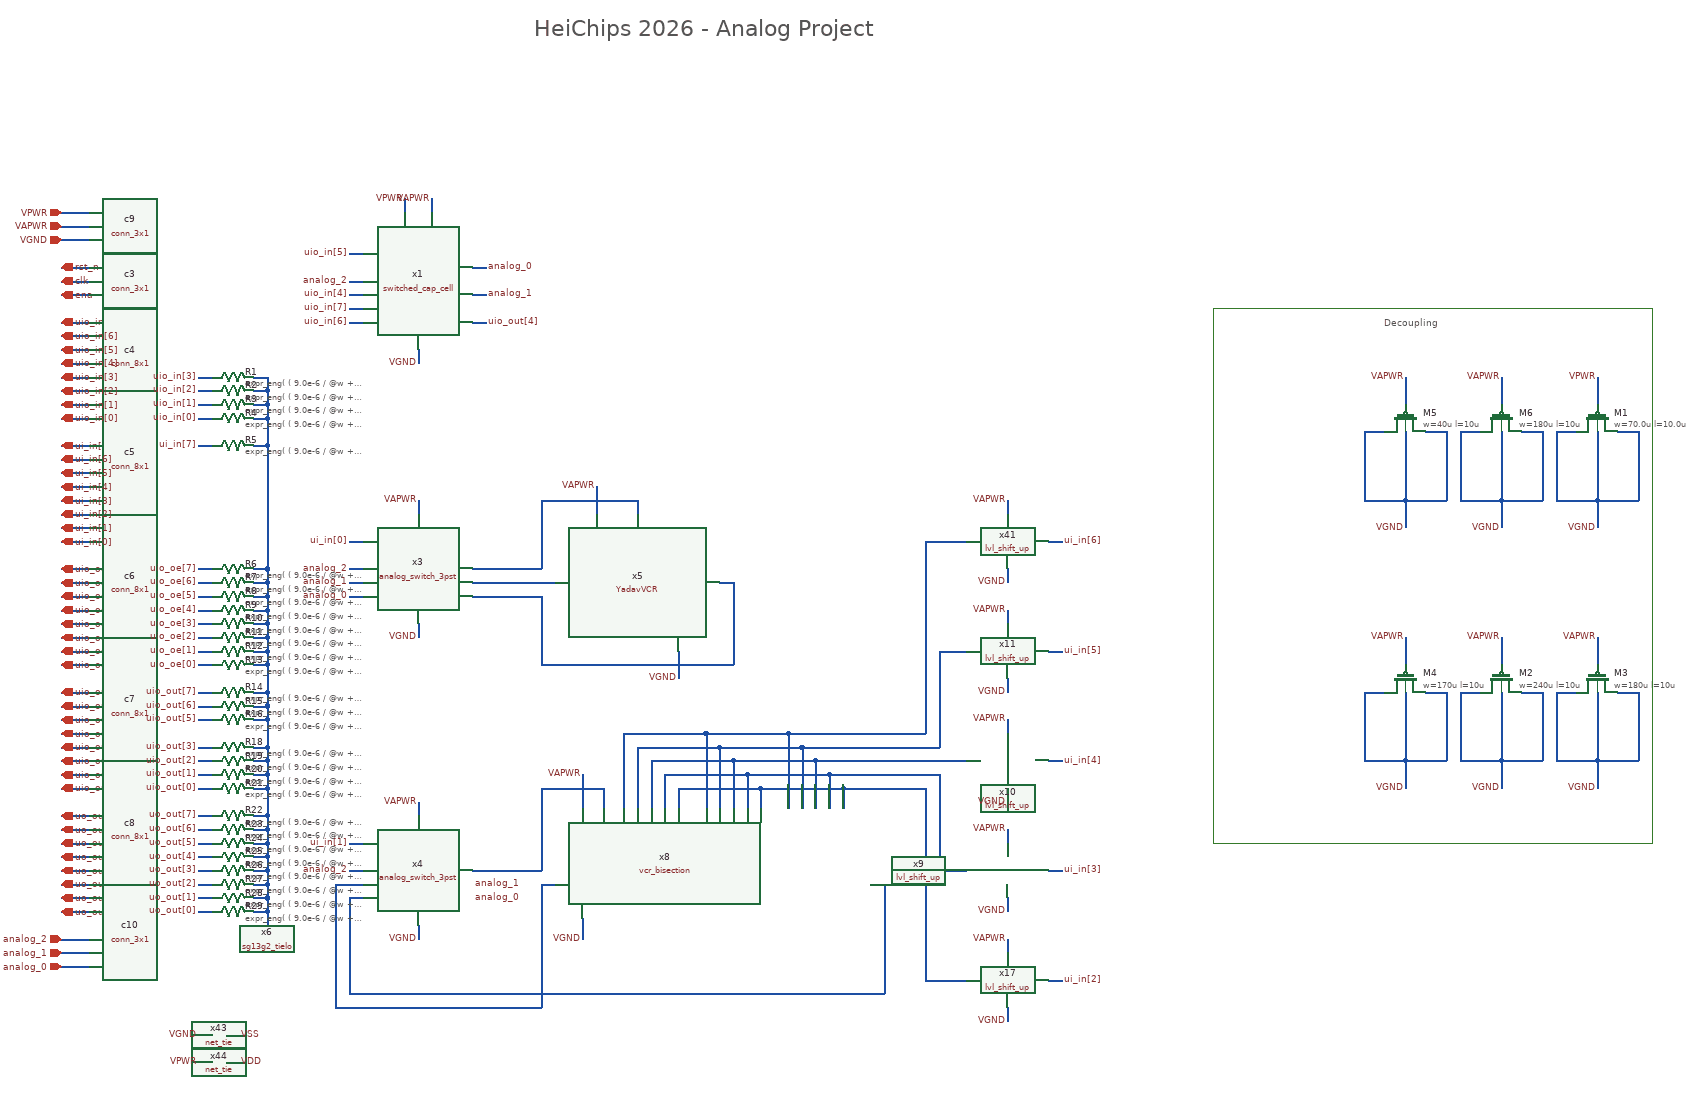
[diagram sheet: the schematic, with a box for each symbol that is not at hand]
v {xschem version=3.4.8RC file_version=1.3}
G {}
K {}
V {}
S {}
F {}
E {}
P 4 1 2050 -1280 {}
P 4 6 1820 -1280 1820 -1280 2460 -1280 2460 -500 1820 -500 1820 -1280 {fill = false
dash = 16}
T {HeiChips 2026 - Analog Project} 830 -1700 0 0 1 1 {}
T {Decoupling} 2070 -1270 0 0 0.4 0.4 {}
N 2380 -800 2380 -760 {lab=VAPWR
}
N 2320 -720 2350 -720 {lab=VGND
}
N 2320 -720 2320 -620 {lab=VGND
}
N 2380 -620 2440 -620 {lab=VGND
}
N 2440 -720 2440 -620 {lab=VGND
}
N 2410 -720 2440 -720 {lab=VGND
}
N 2380 -620 2380 -580 {lab=VGND
}
N 2380 -720 2380 -620 {lab=VGND
}
N 2320 -620 2380 -620 {lab=VGND
}
N 140 -1320 180 -1320 {lab=clk}
N 140 -1300 180 -1300 {lab=ena}
N 140 -1340 180 -1340 {lab=rst_n}
N 140 -1260 180 -1260 {lab=uio_in[7]}
N 140 -1240 180 -1240 {lab=uio_in[6]}
N 140 -1220 180 -1220 {lab=uio_in[5]}
N 140 -1200 180 -1200 {lab=uio_in[4]}
N 140 -1180 180 -1180 {lab=uio_in[3]}
N 140 -1160 180 -1160 {lab=uio_in[2]}
N 140 -1140 180 -1140 {lab=uio_in[1]}
N 140 -1120 180 -1120 {lab=uio_in[0]}
N 140 -1080 180 -1080 {lab=ui_in[7]}
N 140 -1060 180 -1060 {lab=ui_in[6]}
N 140 -1040 180 -1040 {lab=ui_in[5]}
N 140 -1020 180 -1020 {lab=ui_in[4]}
N 140 -1000 180 -1000 {lab=ui_in[3]}
N 140 -980 180 -980 {lab=ui_in[2]}
N 140 -960 180 -960 {lab=ui_in[1]}
N 140 -940 180 -940 {lab=ui_in[0]}
N 140 -900 180 -900 {lab=uio_oe[7]}
N 140 -880 180 -880 {lab=uio_oe[6]}
N 140 -860 180 -860 {lab=uio_oe[5]}
N 140 -840 180 -840 {lab=uio_oe[4]}
N 140 -820 180 -820 {lab=uio_oe[3]}
N 140 -800 180 -800 {lab=uio_oe[2]}
N 140 -780 180 -780 {lab=uio_oe[1]}
N 140 -760 180 -760 {lab=uio_oe[0]}
N 140 -720 180 -720 {lab=uio_out[7]}
N 140 -700 180 -700 {lab=uio_out[6]}
N 140 -680 180 -680 {lab=uio_out[5]}
N 140 -660 180 -660 {lab=uio_out[4]}
N 140 -640 180 -640 {lab=uio_out[3]}
N 140 -620 180 -620 {lab=uio_out[2]}
N 140 -600 180 -600 {lab=uio_out[1]}
N 140 -580 180 -580 {lab=uio_out[0]}
N 140 -540 180 -540 {lab=uo_out[7]}
N 140 -520 180 -520 {lab=uo_out[6]}
N 140 -500 180 -500 {lab=uo_out[5]}
N 140 -480 180 -480 {lab=uo_out[4]}
N 140 -460 180 -460 {lab=uo_out[3]}
N 140 -440 180 -440 {lab=uo_out[2]}
N 140 -420 180 -420 {lab=uo_out[1]}
N 140 -400 180 -400 {lab=uo_out[0]}
N 140 -1400 180 -1400 {lab=VAPWR}
N 140 -1380 180 -1380 {lab=VGND}
N 140 -1420 180 -1420 {lab=VPWR}
N 140 -360 180 -360 {lab=analog_2}
N 140 -340 180 -340 {lab=analog_1}
N 140 -320 180 -320 {lab=analog_0}
N 2380 -1180 2380 -1140 {lab=VPWR
}
N 2320 -1100 2350 -1100 {lab=VGND
}
N 2320 -1100 2320 -1000 {lab=VGND
}
N 2380 -1000 2440 -1000 {lab=VGND
}
N 2440 -1100 2440 -1000 {lab=VGND
}
N 2410 -1100 2440 -1100 {lab=VGND
}
N 2380 -1000 2380 -960 {lab=VGND
}
N 2380 -1100 2380 -1000 {lab=VGND
}
N 2320 -1000 2380 -1000 {lab=VGND
}
N 560 -1360 580 -1360 {lab=uio_in[5]}
N 560 -1300 580 -1300 {lab=uio_in[4]}
N 560 -1280 580 -1280 {lab=uio_in[7]}
N 560 -1260 580 -1260 {lab=uio_in[6]}
N 740 -1260 760 -1260 {lab=uio_out[4]}
N 640 -1440 640 -1420 {lab=VPWR}
N 680 -1440 680 -1420 {lab=VAPWR}
N 660 -1220 660 -1200 {lab=VGND}
N 740 -1340 760 -1340 {lab=analog_0}
N 740 -1300 760 -1300 {lab=analog_1}
N 920 -1020 920 -980 {lab=VAPWR}
N 1040 -780 1040 -740 {lab=VGND}
N 840 -760 1120 -760 {lab=#net1}
N 1100 -880 1120 -880 {lab=#net1}
N 1120 -880 1120 -760 {lab=#net1}
N 740 -880 860 -880 {lab=#net2}
N 660 -1000 660 -980 {lab=VAPWR}
N 660 -820 660 -800 {lab=VGND}
N 560 -860 580 -860 {lab=analog_0}
N 560 -880 580 -880 {lab=analog_1}
N 560 -940 580 -940 {lab=ui_in[0]}
N 560 -900 580 -900 {lab=analog_2}
N 740 -900 840 -900 {lab=#net3}
N 840 -1000 840 -900 {lab=#net3}
N 840 -1000 980 -1000 {lab=#net3}
N 980 -1000 980 -980 {lab=#net3}
N 740 -860 840 -860 {lab=#net1}
N 840 -860 840 -760 {lab=#net1}
N 660 -560 660 -540 {lab=VAPWR
}
N 660 -380 660 -360 {lab=VGND
}
N 560 -500 580 -500 {lab=ui_in[1]
}
N 560 -460 580 -460 {lab=analog_2
}
N 1340 -440 1340 -280 {lab=#net4
}
N 1320 -440 1340 -440 {lab=#net4
}
N 740 -460 840 -460 {lab=#net5
}
N 840 -580 840 -460 {lab=#net5
}
N 840 -580 930 -580 {lab=#net5
}
N 930 -580 930 -550 {lab=#net5
}
N 900 -390 900 -360 {lab=VGND
}
N 900 -600 900 -550 {lab=VAPWR
}
N 560 -1320 580 -1320 {lab=analog_2}
N 340 -400 360 -400 {lab=uo_out[0]
}
N 340 -420 360 -420 {lab=uo_out[1]
}
N 340 -440 360 -440 {lab=uo_out[2]
}
N 340 -460 360 -460 {lab=uo_out[3]
}
N 340 -480 360 -480 {lab=uo_out[4]
}
N 340 -500 360 -500 {lab=uo_out[5]
}
N 340 -520 360 -520 {lab=uo_out[6]
}
N 420 -520 440 -520 {lab=#net6
}
N 440 -520 440 -500 {lab=#net6
}
N 420 -500 440 -500 {lab=#net6
}
N 440 -500 440 -480 {lab=#net6
}
N 420 -480 440 -480 {lab=#net6
}
N 440 -480 440 -460 {lab=#net6
}
N 420 -460 440 -460 {lab=#net6
}
N 440 -460 440 -440 {lab=#net6
}
N 420 -440 440 -440 {lab=#net6
}
N 440 -440 440 -420 {lab=#net6
}
N 420 -420 440 -420 {lab=#net6
}
N 440 -420 440 -400 {lab=#net6
}
N 420 -400 440 -400 {lab=#net6
}
N 440 -400 440 -380 {lab=#net6
}
N 340 -580 360 -580 {lab=uio_out[0]
}
N 340 -600 360 -600 {lab=uio_out[1]
}
N 340 -620 360 -620 {lab=uio_out[2]
}
N 340 -640 360 -640 {lab=uio_out[3]
}
N 340 -680 360 -680 {lab=uio_out[5]
}
N 340 -700 360 -700 {lab=uio_out[6]
}
N 420 -700 440 -700 {lab=#net6
}
N 440 -700 440 -680 {lab=#net6
}
N 420 -680 440 -680 {lab=#net6
}
N 420 -640 440 -640 {lab=#net6
}
N 440 -640 440 -620 {lab=#net6
}
N 420 -620 440 -620 {lab=#net6
}
N 440 -620 440 -600 {lab=#net6
}
N 420 -600 440 -600 {lab=#net6
}
N 440 -600 440 -580 {lab=#net6
}
N 420 -580 440 -580 {lab=#net6
}
N 440 -580 440 -540 {lab=#net6
}
N 340 -720 360 -720 {lab=uio_out[7]
}
N 420 -720 440 -720 {lab=#net6
}
N 340 -1120 360 -1120 {lab=uio_in[0]
}
N 340 -1140 360 -1140 {lab=uio_in[1]
}
N 340 -1160 360 -1160 {lab=uio_in[2]
}
N 340 -1180 360 -1180 {lab=uio_in[3]
}
N 420 -1180 440 -1180 {lab=#net6
}
N 440 -1180 440 -1160 {lab=#net6
}
N 420 -1160 440 -1160 {lab=#net6
}
N 440 -1160 440 -1140 {lab=#net6
}
N 420 -1140 440 -1140 {lab=#net6
}
N 440 -1140 440 -1120 {lab=#net6
}
N 420 -1120 440 -1120 {lab=#net6
}
N 440 -1120 440 -1080 {lab=#net6
}
N 340 -1080 360 -1080 {lab=ui_in[7]
}
N 420 -1080 440 -1080 {lab=#net6
}
N 340 -760 360 -760 {lab=uio_oe[0]
}
N 340 -780 360 -780 {lab=uio_oe[1]
}
N 340 -800 360 -800 {lab=uio_oe[2]
}
N 340 -820 360 -820 {lab=uio_oe[3]
}
N 340 -840 360 -840 {lab=uio_oe[4]
}
N 340 -860 360 -860 {lab=uio_oe[5]
}
N 340 -880 360 -880 {lab=uio_oe[6]
}
N 420 -880 440 -880 {lab=#net6
}
N 440 -880 440 -860 {lab=#net6
}
N 420 -860 440 -860 {lab=#net6
}
N 440 -860 440 -840 {lab=#net6
}
N 420 -840 440 -840 {lab=#net6
}
N 440 -840 440 -820 {lab=#net6
}
N 420 -820 440 -820 {lab=#net6
}
N 440 -820 440 -800 {lab=#net6
}
N 420 -800 440 -800 {lab=#net6
}
N 440 -800 440 -780 {lab=#net6
}
N 420 -780 440 -780 {lab=#net6
}
N 440 -780 440 -760 {lab=#net6
}
N 420 -760 440 -760 {lab=#net6
}
N 440 -760 440 -720 {lab=#net6
}
N 340 -900 360 -900 {lab=uio_oe[7]
}
N 420 -900 440 -900 {lab=#net6
}
N 440 -900 440 -880 {lab=#net6
}
N 440 -720 440 -700 {lab=#net6
}
N 340 -220 360 -220 {lab=VGND}
N 380 -220 400 -220 {lab=VSS}
N 340 -180 360 -180 {lab=VPWR}
N 380 -180 400 -180 {lab=VDD}
N 1200 -660 1400 -660 {lab=#net7}
N 1220 -640 1420 -640 {lab=#net8}
N 1240 -620 1460 -620 {lab=#net9}
N 1260 -600 1420 -600 {lab=#net10}
N 1280 -580 1400 -580 {lab=#net11}
N 440 -1080 440 -900 {lab=#net6
}
N 560 -280 1340 -280 {lab=#net4}
N 560 -420 560 -280 {lab=#net4}
N 560 -420 580 -420 {lab=#net4}
N 840 -440 860 -440 {lab=#net12}
N 840 -440 840 -260 {lab=#net12}
N 540 -260 840 -260 {lab=#net12}
N 540 -440 540 -260 {lab=#net12}
N 540 -440 580 -440 {lab=#net12}
N 1280 -580 1280 -550 {lab=#net11}
N 1160 -580 1280 -580 {lab=#net11}
N 1260 -600 1260 -550 {lab=#net10}
N 1140 -600 1260 -600 {lab=#net10}
N 1240 -620 1240 -550 {lab=#net9}
N 1120 -620 1240 -620 {lab=#net9}
N 1220 -640 1220 -550 {lab=#net8}
N 1100 -640 1220 -640 {lab=#net8}
N 1200 -660 1200 -550 {lab=#net7}
N 1080 -660 1200 -660 {lab=#net7}
N 1160 -580 1160 -550 {lab=#net11}
N 1140 -600 1140 -550 {lab=#net10}
N 1120 -620 1120 -550 {lab=#net9}
N 1100 -640 1100 -550 {lab=#net8}
N 1080 -660 1080 -550 {lab=#net7}
N 1040 -580 1160 -580 {lab=#net11}
N 1020 -600 1140 -600 {lab=#net10}
N 1000 -620 1120 -620 {lab=#net9}
N 1040 -580 1040 -550 {lab=#net11}
N 1020 -600 1020 -550 {lab=#net10}
N 1000 -620 1000 -550 {lab=#net9}
N 980 -640 980 -550 {lab=#net8}
N 980 -640 1100 -640 {lab=#net8}
N 960 -660 960 -550 {lab=#net7}
N 960 -660 1080 -660 {lab=#net7}
N 1520 -520 1520 -500 {lab=VAPWR}
N 1520 -420 1520 -400 {lab=VGND}
N 1520 -680 1520 -660 {lab=VAPWR}
N 1520 -580 1520 -560 {lab=VGND}
N 1520 -840 1520 -820 {lab=VAPWR}
N 1520 -740 1520 -720 {lab=VGND}
N 1520 -360 1520 -340 {lab=VAPWR}
N 1520 -260 1520 -240 {lab=VGND}
N 1520 -1000 1520 -980 {lab=VAPWR}
N 1520 -900 1520 -880 {lab=VGND}
N 1420 -780 1420 -640 {lab=#net8}
N 1420 -780 1460 -780 {lab=#net8}
N 1400 -940 1400 -660 {lab=#net7}
N 1400 -940 1460 -940 {lab=#net7}
N 1420 -600 1420 -460 {lab=#net10}
N 1420 -460 1460 -460 {lab=#net10}
N 1400 -580 1400 -300 {lab=#net11}
N 1400 -300 1460 -300 {lab=#net11}
N 1580 -300 1600 -300 {lab=ui_in[2]}
N 1580 -460 1600 -460 {lab=ui_in[3]}
N 1580 -620 1600 -620 {lab=ui_in[4]}
N 1580 -780 1600 -780 {lab=ui_in[5]}
N 1580 -940 1600 -940 {lab=ui_in[6]}
N 2240 -800 2240 -760 {lab=VAPWR
}
N 2180 -720 2210 -720 {lab=VGND
}
N 2180 -720 2180 -620 {lab=VGND
}
N 2240 -620 2300 -620 {lab=VGND
}
N 2300 -720 2300 -620 {lab=VGND
}
N 2270 -720 2300 -720 {lab=VGND
}
N 2240 -620 2240 -580 {lab=VGND
}
N 2240 -720 2240 -620 {lab=VGND
}
N 2180 -620 2240 -620 {lab=VGND
}
N 340 -540 360 -540 {lab=uo_out[7]}
N 420 -540 440 -540 {lab=#net6}
N 440 -540 440 -520 {lab=#net6}
N 440 -680 440 -640 {lab=#net6}
N 2100 -800 2100 -760 {lab=VAPWR
}
N 2040 -720 2070 -720 {lab=VGND
}
N 2040 -720 2040 -620 {lab=VGND
}
N 2100 -620 2160 -620 {lab=VGND
}
N 2160 -720 2160 -620 {lab=VGND
}
N 2130 -720 2160 -720 {lab=VGND
}
N 2100 -620 2100 -580 {lab=VGND
}
N 2100 -720 2100 -620 {lab=VGND
}
N 2040 -620 2100 -620 {lab=VGND
}
N 2100 -1180 2100 -1140 {lab=VAPWR
}
N 2040 -1100 2070 -1100 {lab=VGND
}
N 2040 -1100 2040 -1000 {lab=VGND
}
N 2100 -1000 2160 -1000 {lab=VGND
}
N 2160 -1100 2160 -1000 {lab=VGND
}
N 2130 -1100 2160 -1100 {lab=VGND
}
N 2100 -1000 2100 -960 {lab=VGND
}
N 2100 -1100 2100 -1000 {lab=VGND
}
N 2040 -1000 2100 -1000 {lab=VGND
}
N 2240 -1180 2240 -1140 {lab=VAPWR
}
N 2180 -1100 2210 -1100 {lab=VGND
}
N 2180 -1100 2180 -1000 {lab=VGND
}
N 2240 -1000 2300 -1000 {lab=VGND
}
N 2300 -1100 2300 -1000 {lab=VGND
}
N 2270 -1100 2300 -1100 {lab=VGND
}
N 2240 -1000 2240 -960 {lab=VGND
}
N 2240 -1100 2240 -1000 {lab=VGND
}
N 2180 -1000 2240 -1000 {lab=VGND
}
C {title-3.sym} 0 0 0 0 {name=l1 author="Simon Dorrer" rev=1.0 lock=true}
C {lab_pin.sym} 2380 -800 1 0 {name=p25 sig_type=std_logic lab=VAPWR
}
C {lab_pin.sym} 2380 -580 3 0 {name=p26 sig_type=std_logic lab=VGND
}
C {devices/ipin.sym} 140 -1340 2 1 {name=p30 lab=rst_n}
C {devices/ipin.sym} 140 -1320 2 1 {name=p31 lab=clk}
C {devices/ipin.sym} 140 -1300 2 1 {name=p32 lab=ena}
C {devices/ipin.sym} 140 -1260 2 1 {name=p33 lab=uio_in[7]}
C {conn_3x1.sym} 200 -1320 0 1 {name=c3 footprint=connector(3,1)}
C {conn_8x1.sym} 200 -1240 0 1 {name=c4 footprint=connector(8,1)}
C {devices/ipin.sym} 140 -1080 2 1 {name=p8 lab=ui_in[7]}
C {conn_8x1.sym} 200 -1060 0 1 {name=c5 footprint=connector(8,1)}
C {devices/opin.sym} 140 -900 2 0 {name=p18 lab=uio_oe[7]}
C {devices/opin.sym} 140 -880 2 0 {name=p27 lab=uio_oe[6]}
C {devices/opin.sym} 140 -860 2 0 {name=p28 lab=uio_oe[5]}
C {devices/opin.sym} 140 -840 2 0 {name=p29 lab=uio_oe[4]}
C {devices/opin.sym} 140 -820 2 0 {name=p41 lab=uio_oe[3]}
C {devices/opin.sym} 140 -800 2 0 {name=p42 lab=uio_oe[2]}
C {devices/opin.sym} 140 -780 2 0 {name=p43 lab=uio_oe[1]}
C {devices/opin.sym} 140 -760 2 0 {name=p44 lab=uio_oe[0]}
C {conn_8x1.sym} 200 -880 0 1 {name=c6 footprint=connector(8,1)}
C {devices/opin.sym} 140 -720 2 0 {name=p45 lab=uio_out[7]}
C {devices/opin.sym} 140 -700 2 0 {name=p46 lab=uio_out[6]}
C {devices/opin.sym} 140 -680 2 0 {name=p47 lab=uio_out[5]}
C {devices/opin.sym} 140 -660 2 0 {name=p48 lab=uio_out[4]}
C {devices/opin.sym} 140 -640 2 0 {name=p49 lab=uio_out[3]}
C {devices/opin.sym} 140 -620 2 0 {name=p50 lab=uio_out[2]}
C {devices/opin.sym} 140 -600 2 0 {name=p51 lab=uio_out[1]}
C {devices/opin.sym} 140 -580 2 0 {name=p52 lab=uio_out[0]}
C {conn_8x1.sym} 200 -700 0 1 {name=c7 footprint=connector(8,1)}
C {devices/opin.sym} 140 -540 2 0 {name=p53 lab=uo_out[7]}
C {devices/opin.sym} 140 -520 2 0 {name=p54 lab=uo_out[6]}
C {devices/opin.sym} 140 -500 2 0 {name=p55 lab=uo_out[5]}
C {devices/opin.sym} 140 -480 2 0 {name=p56 lab=uo_out[4]}
C {devices/opin.sym} 140 -460 2 0 {name=p57 lab=uo_out[3]}
C {devices/opin.sym} 140 -440 2 0 {name=p58 lab=uo_out[2]}
C {devices/opin.sym} 140 -420 2 0 {name=p59 lab=uo_out[1]}
C {devices/opin.sym} 140 -400 2 0 {name=p60 lab=uo_out[0]}
C {conn_8x1.sym} 200 -520 0 1 {name=c8 footprint=connector(8,1)}
C {conn_3x1.sym} 200 -1400 0 1 {name=c9 footprint=connector(3,1)}
C {devices/iopin.sym} 140 -1420 2 0 {name=p61 lab=VPWR}
C {devices/iopin.sym} 140 -1380 2 0 {name=p62 lab=VGND}
C {devices/iopin.sym} 140 -1400 2 0 {name=p63 lab=VAPWR}
C {devices/ipin.sym} 140 -1060 2 1 {name=p9 lab=ui_in[6]}
C {devices/ipin.sym} 140 -1040 2 1 {name=p12 lab=ui_in[5]}
C {devices/ipin.sym} 140 -1020 2 1 {name=p13 lab=ui_in[4]}
C {devices/ipin.sym} 140 -1000 2 1 {name=p14 lab=ui_in[3]}
C {devices/ipin.sym} 140 -980 2 1 {name=p15 lab=ui_in[2]}
C {devices/ipin.sym} 140 -960 2 1 {name=p16 lab=ui_in[1]}
C {devices/ipin.sym} 140 -940 2 1 {name=p17 lab=ui_in[0]}
C {devices/ipin.sym} 140 -1240 2 1 {name=p34 lab=uio_in[6]}
C {devices/ipin.sym} 140 -1220 2 1 {name=p35 lab=uio_in[5]}
C {devices/ipin.sym} 140 -1200 2 1 {name=p36 lab=uio_in[4]}
C {devices/ipin.sym} 140 -1180 2 1 {name=p37 lab=uio_in[3]}
C {devices/ipin.sym} 140 -1160 2 1 {name=p38 lab=uio_in[2]}
C {devices/ipin.sym} 140 -1140 2 1 {name=p39 lab=uio_in[1]}
C {devices/ipin.sym} 140 -1120 2 1 {name=p40 lab=uio_in[0]}
C {conn_3x1.sym} 200 -340 0 1 {name=c10 footprint=connector(3,1)}
C {devices/iopin.sym} 140 -360 2 0 {name=p64 lab=analog_2}
C {devices/iopin.sym} 140 -340 2 0 {name=p65 lab=analog_1}
C {devices/iopin.sym} 140 -320 2 0 {name=p66 lab=analog_0}
C {lab_pin.sym} 2380 -1180 1 0 {name=p3 sig_type=std_logic lab=VPWR
}
C {lab_pin.sym} 2380 -960 3 0 {name=p4 sig_type=std_logic lab=VGND
}
C {sg13cmos5l_pr/sg13_lv_pmos.sym} 2380 -1120 1 0 {name=M1
l=10.0u
w=70.0u
ng=7
m=1
mm_ok=1
model=sg13_lv_pmos
spiceprefix=X
}
C {lab_pin.sym} 560 -1320 0 0 {name=p6 sig_type=std_logic lab=analog_2}
C {lab_pin.sym} 760 -1300 0 1 {name=p10 sig_type=std_logic lab=analog_1}
C {switched_cap_cell.sym} 660 -1320 0 0 {name=x1}
C {YadavVCR.sym} 980 -880 0 0 {name=x5}
C {lab_pin.sym} 1600 -620 0 1 {name=p20 sig_type=std_logic lab=ui_in[4]}
C {lab_pin.sym} 1600 -780 0 1 {name=p21 sig_type=std_logic lab=ui_in[5]}
C {lab_pin.sym} 1600 -940 0 1 {name=p22 sig_type=std_logic lab=ui_in[6]}
C {lab_pin.sym} 340 -1080 0 0 {name=p23 sig_type=std_logic lab=ui_in[7]
}
C {lab_pin.sym} 760 -1340 0 1 {name=p24 sig_type=std_logic lab=analog_0}
C {lab_pin.sym} 340 -540 0 0 {name=p67 sig_type=std_logic lab=uo_out[7]
}
C {lab_pin.sym} 660 -1200 3 0 {name=p68 sig_type=std_logic lab=VGND}
C {lab_pin.sym} 680 -1440 1 0 {name=p69 sig_type=std_logic lab=VAPWR}
C {lab_pin.sym} 640 -1440 1 0 {name=p70 sig_type=std_logic lab=VPWR}
C {lab_pin.sym} 1040 -740 3 0 {name=p11 sig_type=std_logic lab=VGND}
C {lab_pin.sym} 920 -1020 1 0 {name=p19 sig_type=std_logic lab=VAPWR}
C {lab_pin.sym} 660 -800 3 0 {name=p1 sig_type=std_logic lab=VGND}
C {lab_pin.sym} 660 -1000 1 0 {name=p2 sig_type=std_logic lab=VAPWR}
C {lab_pin.sym} 560 -900 0 0 {name=p5 sig_type=std_logic lab=analog_2}
C {lab_pin.sym} 560 -880 0 0 {name=p7 sig_type=std_logic lab=analog_1}
C {lab_pin.sym} 1600 -300 0 1 {name=p71 sig_type=std_logic lab=ui_in[2]
}
C {analog_switch_3pst.sym} 660 -900 0 0 {name=x3}
C {lab_pin.sym} 560 -860 0 0 {name=p72 sig_type=std_logic lab=analog_0}
C {lab_pin.sym} 660 -360 3 0 {name=p73 sig_type=std_logic lab=VGND
}
C {lab_pin.sym} 660 -560 1 0 {name=p74 sig_type=std_logic lab=VAPWR
}
C {lab_pin.sym} 560 -460 0 0 {name=p75 sig_type=std_logic lab=analog_2
}
C {lab_pin.sym} 740 -440 0 1 {name=p76 sig_type=std_logic lab=analog_1
}
C {lab_pin.sym} 1600 -460 0 1 {name=p77 sig_type=std_logic lab=ui_in[3]}
C {analog_switch_3pst.sym} 660 -460 0 0 {name=x4
}
C {lab_pin.sym} 740 -420 0 1 {name=p78 sig_type=std_logic lab=analog_0
}
C {lab_pin.sym} 900 -360 3 0 {name=p79 sig_type=std_logic lab=VGND
}
C {lab_pin.sym} 900 -600 1 0 {name=p80 sig_type=std_logic lab=VAPWR
}
C {lab_pin.sym} 560 -500 0 0 {name=p82 sig_type=std_logic lab=ui_in[1]}
C {lab_pin.sym} 560 -940 0 0 {name=p83 sig_type=std_logic lab=ui_in[0]}
C {lab_pin.sym} 340 -520 0 0 {name=p84 sig_type=std_logic lab=uo_out[6]
}
C {lab_pin.sym} 340 -500 0 0 {name=p85 sig_type=std_logic lab=uo_out[5]
}
C {lab_pin.sym} 340 -480 0 0 {name=p86 sig_type=std_logic lab=uo_out[4]
}
C {lab_pin.sym} 340 -460 0 0 {name=p87 sig_type=std_logic lab=uo_out[3]
}
C {lab_pin.sym} 340 -440 0 0 {name=p88 sig_type=std_logic lab=uo_out[2]
}
C {lab_pin.sym} 340 -420 0 0 {name=p89 sig_type=std_logic lab=uo_out[1]
}
C {lab_pin.sym} 340 -400 0 0 {name=p90 sig_type=std_logic lab=uo_out[0]
}
C {lab_pin.sym} 340 -700 0 0 {name=p91 sig_type=std_logic lab=uio_out[6]
}
C {lab_pin.sym} 340 -680 0 0 {name=p92 sig_type=std_logic lab=uio_out[5]
}
C {lab_pin.sym} 760 -1260 0 1 {name=p93 sig_type=std_logic lab=uio_out[4]
}
C {lab_pin.sym} 340 -640 0 0 {name=p94 sig_type=std_logic lab=uio_out[3]
}
C {lab_pin.sym} 340 -620 0 0 {name=p95 sig_type=std_logic lab=uio_out[2]
}
C {lab_pin.sym} 340 -600 0 0 {name=p96 sig_type=std_logic lab=uio_out[1]
}
C {lab_pin.sym} 340 -580 0 0 {name=p97 sig_type=std_logic lab=uio_out[0]
}
C {lab_pin.sym} 340 -720 0 0 {name=p98 sig_type=std_logic lab=uio_out[7]
}
C {lab_pin.sym} 340 -1160 0 0 {name=p99 sig_type=std_logic lab=uio_in[2]
}
C {lab_pin.sym} 340 -1140 0 0 {name=p100 sig_type=std_logic lab=uio_in[1]
}
C {lab_pin.sym} 340 -1120 0 0 {name=p101 sig_type=std_logic lab=uio_in[0]
}
C {lab_pin.sym} 560 -1260 0 0 {name=p102 sig_type=std_logic lab=uio_in[6]}
C {lab_pin.sym} 560 -1360 0 0 {name=p103 sig_type=std_logic lab=uio_in[5]}
C {lab_pin.sym} 560 -1300 0 0 {name=p104 sig_type=std_logic lab=uio_in[4]}
C {lab_pin.sym} 560 -1280 0 0 {name=p105 sig_type=std_logic lab=uio_in[7]}
C {lab_pin.sym} 340 -1180 0 0 {name=p106 sig_type=std_logic lab=uio_in[3]
}
C {lab_pin.sym} 340 -800 0 0 {name=p107 sig_type=std_logic lab=uio_oe[2]
}
C {lab_pin.sym} 340 -780 0 0 {name=p108 sig_type=std_logic lab=uio_oe[1]
}
C {lab_pin.sym} 340 -760 0 0 {name=p109 sig_type=std_logic lab=uio_oe[0]
}
C {lab_pin.sym} 340 -880 0 0 {name=p110 sig_type=std_logic lab=uio_oe[6]
}
C {lab_pin.sym} 340 -860 0 0 {name=p111 sig_type=std_logic lab=uio_oe[5]
}
C {lab_pin.sym} 340 -840 0 0 {name=p112 sig_type=std_logic lab=uio_oe[4]
}
C {lab_pin.sym} 340 -900 0 0 {name=p113 sig_type=std_logic lab=uio_oe[7]
}
C {lab_pin.sym} 340 -820 0 0 {name=p114 sig_type=std_logic lab=uio_oe[3]
}
C {net_tie.sym} 360 -220 0 0 {name=x43}
C {lab_pin.sym} 340 -220 0 0 {name=p115 sig_type=std_logic lab=VGND
}
C {lab_pin.sym} 400 -220 0 1 {name=p116 sig_type=std_logic lab=VSS
}
C {net_tie.sym} 360 -180 0 0 {name=x44}
C {lab_pin.sym} 340 -180 0 0 {name=p117 sig_type=std_logic lab=VPWR
}
C {lab_pin.sym} 400 -180 0 1 {name=p118 sig_type=std_logic lab=VDD
}
C {/home/noah/Documents/freizeit/heichips/heichips26-voltage-controlled-resistor/IHP-Open-PDK/ihp-sg13g2/libs.ref/sg13g2_stdcell/sym/xschem/sg13g2_tielo.sym} 440 -380 0 0 {name=x6 VDD=VDD VSS=VSS prefix=sg13g2_ spice_ignore=true}
C {vcr_bisection.sym} 880 -410 0 0 {name=x8}
C {lvl_shift_up.sym} 1520 -460 0 1 {name=x9}
C {lab_pin.sym} 1520 -400 0 0 {name=p81 sig_type=std_logic lab=VGND}
C {lab_pin.sym} 1520 -520 0 0 {name=p119 sig_type=std_logic lab=VAPWR}
C {lvl_shift_up.sym} 1520 -620 0 1 {name=x10}
C {lab_pin.sym} 1520 -560 0 0 {name=p120 sig_type=std_logic lab=VGND}
C {lab_pin.sym} 1520 -680 0 0 {name=p121 sig_type=std_logic lab=VAPWR}
C {lvl_shift_up.sym} 1520 -780 0 1 {name=x11}
C {lab_pin.sym} 1520 -720 0 0 {name=p122 sig_type=std_logic lab=VGND}
C {lab_pin.sym} 1520 -840 0 0 {name=p123 sig_type=std_logic lab=VAPWR}
C {lvl_shift_up.sym} 1520 -300 0 1 {name=x17}
C {lab_pin.sym} 1520 -240 0 0 {name=p124 sig_type=std_logic lab=VGND}
C {lab_pin.sym} 1520 -360 0 0 {name=p125 sig_type=std_logic lab=VAPWR}
C {lvl_shift_up.sym} 1520 -940 0 1 {name=x41}
C {lab_pin.sym} 1520 -880 0 0 {name=p126 sig_type=std_logic lab=VGND}
C {lab_pin.sym} 1520 -1000 0 0 {name=p127 sig_type=std_logic lab=VAPWR}
C {sg13_lv_pmos.sym} 2380 -740 1 0 {name=M3
l=10u
w=180u
ng=18
m=1
model=sg13_hv_pmos
spiceprefix=X
}
C {lab_pin.sym} 2240 -800 1 0 {name=p128 sig_type=std_logic lab=VAPWR
}
C {lab_pin.sym} 2240 -580 3 0 {name=p129 sig_type=std_logic lab=VGND
}
C {sg13_lv_pmos.sym} 2240 -740 1 0 {name=M2
l=10u
w=240u
ng=24
m=1
model=sg13_hv_pmos
spiceprefix=X
}
C {sg13cmos5l_pr/rsil.sym} 390 -1180 3 0 {name=R1
w=0.5e-6
l=0.5e-6
model=rsil
body=VGND
spiceprefix=X
 m=1
  mm_ok=1
value="expr_eng(  ( 9.0e-6 / @w + 7.0 * ( @l ) / ( @w + 1.0e-8 ) ) / @m  )"
}
C {sg13cmos5l_pr/rsil.sym} 390 -1160 3 0 {name=R2
w=0.5e-6
l=0.5e-6
model=rsil
body=VGND
spiceprefix=X
 m=1
  mm_ok=1
value="expr_eng(  ( 9.0e-6 / @w + 7.0 * ( @l ) / ( @w + 1.0e-8 ) ) / @m  )"
}
C {sg13cmos5l_pr/rsil.sym} 390 -1140 3 0 {name=R3
w=0.5e-6
l=0.5e-6
model=rsil
body=VGND
spiceprefix=X
 m=1
  mm_ok=1
value="expr_eng(  ( 9.0e-6 / @w + 7.0 * ( @l ) / ( @w + 1.0e-8 ) ) / @m  )"
}
C {sg13cmos5l_pr/rsil.sym} 390 -1120 3 0 {name=R4
w=0.5e-6
l=0.5e-6
model=rsil
body=VGND
spiceprefix=X
 m=1
  mm_ok=1
value="expr_eng(  ( 9.0e-6 / @w + 7.0 * ( @l ) / ( @w + 1.0e-8 ) ) / @m  )"
}
C {sg13cmos5l_pr/rsil.sym} 390 -1080 3 0 {name=R5
w=0.5e-6
l=0.5e-6
model=rsil
body=VGND
spiceprefix=X
 m=1
  mm_ok=1
value="expr_eng(  ( 9.0e-6 / @w + 7.0 * ( @l ) / ( @w + 1.0e-8 ) ) / @m  )"
}
C {sg13cmos5l_pr/rsil.sym} 390 -900 3 0 {name=R6
w=0.5e-6
l=0.5e-6
model=rsil
body=VGND
spiceprefix=X
 m=1
  mm_ok=1
value="expr_eng(  ( 9.0e-6 / @w + 7.0 * ( @l ) / ( @w + 1.0e-8 ) ) / @m  )"
}
C {sg13cmos5l_pr/rsil.sym} 390 -880 3 0 {name=R7
w=0.5e-6
l=0.5e-6
model=rsil
body=VGND
spiceprefix=X
 m=1
  mm_ok=1
value="expr_eng(  ( 9.0e-6 / @w + 7.0 * ( @l ) / ( @w + 1.0e-8 ) ) / @m  )"
}
C {sg13cmos5l_pr/rsil.sym} 390 -860 3 0 {name=R8
w=0.5e-6
l=0.5e-6
model=rsil
body=VGND
spiceprefix=X
 m=1
  mm_ok=1
value="expr_eng(  ( 9.0e-6 / @w + 7.0 * ( @l ) / ( @w + 1.0e-8 ) ) / @m  )"
}
C {sg13cmos5l_pr/rsil.sym} 390 -840 3 0 {name=R9
w=0.5e-6
l=0.5e-6
model=rsil
body=VGND
spiceprefix=X
 m=1
  mm_ok=1
value="expr_eng(  ( 9.0e-6 / @w + 7.0 * ( @l ) / ( @w + 1.0e-8 ) ) / @m  )"
}
C {sg13cmos5l_pr/rsil.sym} 390 -820 3 0 {name=R10
w=0.5e-6
l=0.5e-6
model=rsil
body=VGND
spiceprefix=X
 m=1
  mm_ok=1
value="expr_eng(  ( 9.0e-6 / @w + 7.0 * ( @l ) / ( @w + 1.0e-8 ) ) / @m  )"
}
C {sg13cmos5l_pr/rsil.sym} 390 -800 3 0 {name=R11
w=0.5e-6
l=0.5e-6
model=rsil
body=VGND
spiceprefix=X
 m=1
  mm_ok=1
value="expr_eng(  ( 9.0e-6 / @w + 7.0 * ( @l ) / ( @w + 1.0e-8 ) ) / @m  )"
}
C {sg13cmos5l_pr/rsil.sym} 390 -780 3 0 {name=R12
w=0.5e-6
l=0.5e-6
model=rsil
body=VGND
spiceprefix=X
 m=1
  mm_ok=1
value="expr_eng(  ( 9.0e-6 / @w + 7.0 * ( @l ) / ( @w + 1.0e-8 ) ) / @m  )"
}
C {sg13cmos5l_pr/rsil.sym} 390 -760 3 0 {name=R13
w=0.5e-6
l=0.5e-6
model=rsil
body=VGND
spiceprefix=X
 m=1
  mm_ok=1
value="expr_eng(  ( 9.0e-6 / @w + 7.0 * ( @l ) / ( @w + 1.0e-8 ) ) / @m  )"
}
C {sg13cmos5l_pr/rsil.sym} 390 -720 3 0 {name=R14
w=0.5e-6
l=0.5e-6
model=rsil
body=VGND
spiceprefix=X
 m=1
  mm_ok=1
value="expr_eng(  ( 9.0e-6 / @w + 7.0 * ( @l ) / ( @w + 1.0e-8 ) ) / @m  )"
}
C {sg13cmos5l_pr/rsil.sym} 390 -700 3 0 {name=R15
w=0.5e-6
l=0.5e-6
model=rsil
body=VGND
spiceprefix=X
 m=1
  mm_ok=1
value="expr_eng(  ( 9.0e-6 / @w + 7.0 * ( @l ) / ( @w + 1.0e-8 ) ) / @m  )"
}
C {sg13cmos5l_pr/rsil.sym} 390 -680 3 0 {name=R16
w=0.5e-6
l=0.5e-6
model=rsil
body=VGND
spiceprefix=X
 m=1
  mm_ok=1
value="expr_eng(  ( 9.0e-6 / @w + 7.0 * ( @l ) / ( @w + 1.0e-8 ) ) / @m  )"
}
C {sg13cmos5l_pr/rsil.sym} 390 -640 3 0 {name=R18
w=0.5e-6
l=0.5e-6
model=rsil
body=VGND
spiceprefix=X
 m=1
  mm_ok=1
value="expr_eng(  ( 9.0e-6 / @w + 7.0 * ( @l ) / ( @w + 1.0e-8 ) ) / @m  )"
}
C {sg13cmos5l_pr/rsil.sym} 390 -620 3 0 {name=R19
w=0.5e-6
l=0.5e-6
model=rsil
body=VGND
spiceprefix=X
 m=1
  mm_ok=1
value="expr_eng(  ( 9.0e-6 / @w + 7.0 * ( @l ) / ( @w + 1.0e-8 ) ) / @m  )"
}
C {sg13cmos5l_pr/rsil.sym} 390 -600 3 0 {name=R20
w=0.5e-6
l=0.5e-6
model=rsil
body=VGND
spiceprefix=X
 m=1
  mm_ok=1
value="expr_eng(  ( 9.0e-6 / @w + 7.0 * ( @l ) / ( @w + 1.0e-8 ) ) / @m  )"
}
C {sg13cmos5l_pr/rsil.sym} 390 -580 3 0 {name=R21
w=0.5e-6
l=0.5e-6
model=rsil
body=VGND
spiceprefix=X
 m=1
  mm_ok=1
value="expr_eng(  ( 9.0e-6 / @w + 7.0 * ( @l ) / ( @w + 1.0e-8 ) ) / @m  )"
}
C {sg13cmos5l_pr/rsil.sym} 390 -540 3 0 {name=R22
w=0.5e-6
l=0.5e-6
model=rsil
body=VGND
spiceprefix=X
 m=1
  mm_ok=1
value="expr_eng(  ( 9.0e-6 / @w + 7.0 * ( @l ) / ( @w + 1.0e-8 ) ) / @m  )"
}
C {sg13cmos5l_pr/rsil.sym} 390 -520 3 0 {name=R23
w=0.5e-6
l=0.5e-6
model=rsil
body=VGND
spiceprefix=X
 m=1
  mm_ok=1
value="expr_eng(  ( 9.0e-6 / @w + 7.0 * ( @l ) / ( @w + 1.0e-8 ) ) / @m  )"
}
C {sg13cmos5l_pr/rsil.sym} 390 -500 3 0 {name=R24
w=0.5e-6
l=0.5e-6
model=rsil
body=VGND
spiceprefix=X
 m=1
  mm_ok=1
value="expr_eng(  ( 9.0e-6 / @w + 7.0 * ( @l ) / ( @w + 1.0e-8 ) ) / @m  )"
}
C {sg13cmos5l_pr/rsil.sym} 390 -480 3 0 {name=R25
w=0.5e-6
l=0.5e-6
model=rsil
body=VGND
spiceprefix=X
 m=1
  mm_ok=1
value="expr_eng(  ( 9.0e-6 / @w + 7.0 * ( @l ) / ( @w + 1.0e-8 ) ) / @m  )"
}
C {sg13cmos5l_pr/rsil.sym} 390 -460 3 0 {name=R26
w=0.5e-6
l=0.5e-6
model=rsil
body=VGND
spiceprefix=X
 m=1
  mm_ok=1
value="expr_eng(  ( 9.0e-6 / @w + 7.0 * ( @l ) / ( @w + 1.0e-8 ) ) / @m  )"
}
C {sg13cmos5l_pr/rsil.sym} 390 -440 3 0 {name=R27
w=0.5e-6
l=0.5e-6
model=rsil
body=VGND
spiceprefix=X
 m=1
  mm_ok=1
value="expr_eng(  ( 9.0e-6 / @w + 7.0 * ( @l ) / ( @w + 1.0e-8 ) ) / @m  )"
}
C {sg13cmos5l_pr/rsil.sym} 390 -420 3 0 {name=R28
w=0.5e-6
l=0.5e-6
model=rsil
body=VGND
spiceprefix=X
 m=1
  mm_ok=1
value="expr_eng(  ( 9.0e-6 / @w + 7.0 * ( @l ) / ( @w + 1.0e-8 ) ) / @m  )"
}
C {sg13cmos5l_pr/rsil.sym} 390 -400 3 0 {name=R29
w=0.5e-6
l=0.5e-6
model=rsil
body=VGND
spiceprefix=X
 m=1
  mm_ok=1
value="expr_eng(  ( 9.0e-6 / @w + 7.0 * ( @l ) / ( @w + 1.0e-8 ) ) / @m  )"
}
C {lab_pin.sym} 2100 -800 1 0 {name=p130 sig_type=std_logic lab=VAPWR
}
C {lab_pin.sym} 2100 -580 3 0 {name=p131 sig_type=std_logic lab=VGND
}
C {sg13_lv_pmos.sym} 2100 -740 1 0 {name=M4
l=10u
w=170u
ng=17
m=1
model=sg13_hv_pmos
spiceprefix=X
}
C {lab_pin.sym} 2100 -1180 1 0 {name=p132 sig_type=std_logic lab=VAPWR
}
C {lab_pin.sym} 2100 -960 3 0 {name=p133 sig_type=std_logic lab=VGND
}
C {sg13_lv_pmos.sym} 2100 -1120 1 0 {name=M5
l=10u
w=40u
ng=4
m=1
model=sg13_hv_pmos
spiceprefix=X
}
C {lab_pin.sym} 2240 -1180 1 0 {name=p134 sig_type=std_logic lab=VAPWR
}
C {lab_pin.sym} 2240 -960 3 0 {name=p135 sig_type=std_logic lab=VGND
}
C {sg13_lv_pmos.sym} 2240 -1120 1 0 {name=M6
l=10u
w=180u
ng=18
m=1
model=sg13_hv_pmos
spiceprefix=X
}
